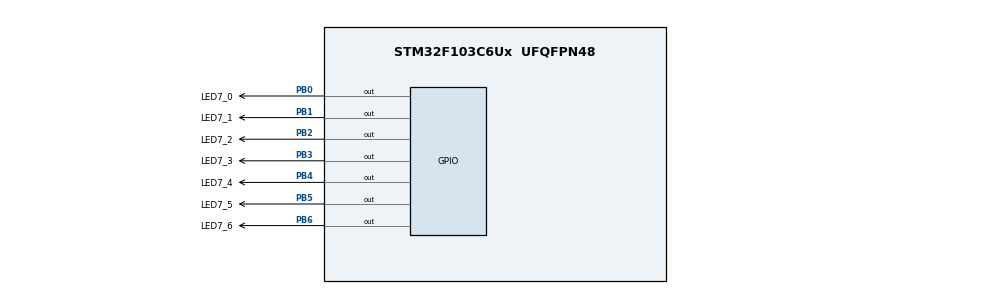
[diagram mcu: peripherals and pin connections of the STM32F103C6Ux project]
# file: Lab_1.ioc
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Mcu.Family=STM32F1
Mcu.Name=STM32F103C6Ux
Mcu.Package=UFQFPN48
NVIC.PriorityGroup=NVIC_PRIORITYGROUP_4
PB0.GPIO_Label=LED7_0
PB0.Signal=GPIO_Output
PB1.GPIO_Label=LED7_1
PB1.Signal=GPIO_Output
PB2.GPIO_Label=LED7_2
PB2.Signal=GPIO_Output
PB3.GPIO_Label=LED7_3
PB3.Signal=GPIO_Output
PB4.GPIO_Label=LED7_4
PB4.Signal=GPIO_Output
PB5.GPIO_Label=LED7_5
PB5.Signal=GPIO_Output
PB6.GPIO_Label=LED7_6
PB6.Signal=GPIO_Output
ProjectManager.HeapSize=0x200
ProjectManager.StackSize=0x400
ProjectManager.TargetToolchain=STM32CubeIDE
RCC.APB1Freq_Value=8000000
RCC.APB2Freq_Value=8000000
VP_SYS_VS_ND.Mode=No_Debug
board=custom

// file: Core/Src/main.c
/* USER CODE BEGIN Header */
/**
  ******************************************************************************
  * @file           : main.c
  * @brief          : Main program body
  ******************************************************************************
  * @attention
  *
  * <h2><center>&copy; Copyright (c) 2023 STMicroelectronics.
  * All rights reserved.</center></h2>
  *
  * This software component is licensed by ST under BSD 3-Clause license,
  * the "License"; You may not use this file except in compliance with the
  * License. You may obtain a copy of the License at:
  *                        opensource.org/licenses/BSD-3-Clause
  *
  ******************************************************************************
  */
/* USER CODE END Header */
#include "main.h"

void SystemClock_Config(void);
static void MX_GPIO_Init(void);
void clearAllClock();
void setNumberOnClock(int num);
void clearNumberOnClock(int num);

int main(void)
{

  /* MCU Configuration--------------------------------------------------------*/

  /* Reset of all peripherals, Initializes the Flash interface and the Systick. */
  HAL_Init();

  /* Configure the system clock */
  SystemClock_Config();

  /* Initialize all configured peripherals */
  MX_GPIO_Init();

  /* Infinite loop */
  //Quy ước:
  /* Mỗi 5 giây -> LED hiển thị giây di chuyển 1đv*/
  /* Mỗi 60 giây (LED hiển thị giây quay 1 vòng) -> LED hiển thị phút di chuyển 1đv */
  /* LED hiển thị phút quay 1 vòng -> LED hiển thị giờ di chuyển 1đv */
  /* không giống với thực tế vì để giảm thời gian kiểm tra */
  clearAllClock();
  int second = 0, minute = 10, hour = 5; // start at 5:10:00
  int counter = 0;
  while (1)
  {
	  setNumberOnClock(second);
	  setNumberOnClock(minute);
	  setNumberOnClock(hour);
	  HAL_Delay(1000);
	  counter ++;
	  if(counter >= 5){
		  counter = 0;
		  clearNumberOnClock(second++);
	  }
	  if(second >= 12){
		  second = 0;
		  clearNumberOnClock(minute++);
	  }
	  if(minute >= 12){
		  minute = 0;
		  clearNumberOnClock(hour++);
	  }
	  if(hour >= 12) hour = 0;
  }
}

void clearAllClock(){
	HAL_GPIO_WritePin (GPIOA , LED_1_Pin | LED_2_Pin | LED_3_Pin | LED_4_Pin | LED_5_Pin | LED_6_Pin | LED_7_Pin | LED_8_Pin | LED_9_Pin | LED_10_Pin | LED_11_Pin | LED_12_Pin , 1);
}

void setNumberOnClock(int num){
	switch(num){
	case 0:
		HAL_GPIO_WritePin(GPIOA, LED_12_Pin, 0);
		break;
	case 1:
		HAL_GPIO_WritePin(GPIOA, LED_1_Pin, 0);
		break;
	case 2:
		HAL_GPIO_WritePin(GPIOA, LED_2_Pin, 0);
		break;
	case 3:
		HAL_GPIO_WritePin(GPIOA, LED_3_Pin, 0);
		break;
	case 4:
		HAL_GPIO_WritePin(GPIOA, LED_4_Pin, 0);
		break;
	case 5:
		HAL_GPIO_WritePin(GPIOA, LED_5_Pin, 0);
		break;
	case 6:
		HAL_GPIO_WritePin(GPIOA, LED_6_Pin, 0);
		break;
	case 7:
		HAL_GPIO_WritePin(GPIOA, LED_7_Pin, 0);
		break;
	case 8:
		HAL_GPIO_WritePin(GPIOA, LED_8_Pin, 0);
		break;
	case 9:
		HAL_GPIO_WritePin(GPIOA, LED_9_Pin, 0);
		break;
	case 10:
		HAL_GPIO_WritePin(GPIOA, LED_10_Pin, 0);
		break;
	case 11:
		HAL_GPIO_WritePin(GPIOA, LED_11_Pin, 0);
		break;
	default:
		break;
	}
}

void clearNumberOnClock(int num){
	switch(num){
	case 0:
		HAL_GPIO_WritePin(GPIOA, LED_12_Pin, 1);
		break;
	case 1:
		HAL_GPIO_WritePin(GPIOA, LED_1_Pin, 1);
		break;
	case 2:
		HAL_GPIO_WritePin(GPIOA, LED_2_Pin, 1);
		break;
	case 3:
		HAL_GPIO_WritePin(GPIOA, LED_3_Pin, 1);
		break;
	case 4:
		HAL_GPIO_WritePin(GPIOA, LED_4_Pin, 1);
		break;
	case 5:
		HAL_GPIO_WritePin(GPIOA, LED_5_Pin, 1);
		break;
	case 6:
		HAL_GPIO_WritePin(GPIOA, LED_6_Pin, 1);
		break;
	case 7:
		HAL_GPIO_WritePin(GPIOA, LED_7_Pin, 1);
		break;
	case 8:
		HAL_GPIO_WritePin(GPIOA, LED_8_Pin, 1);
		break;
	case 9:
		HAL_GPIO_WritePin(GPIOA, LED_9_Pin, 1);
		break;
	case 10:
		HAL_GPIO_WritePin(GPIOA, LED_10_Pin, 1);
		break;
	case 11:
		HAL_GPIO_WritePin(GPIOA, LED_11_Pin, 1);
		break;
	default:
		break;
	}
}

void SystemClock_Config(void)
{
  RCC_OscInitTypeDef RCC_OscInitStruct = {0};
  RCC_ClkInitTypeDef RCC_ClkInitStruct = {0};

  /** Initializes the RCC Oscillators according to the specified parameters
  * in the RCC_OscInitTypeDef structure.
  */
  RCC_OscInitStruct.OscillatorType = RCC_OSCILLATORTYPE_HSI;
  RCC_OscInitStruct.HSIState = RCC_HSI_ON;
  RCC_OscInitStruct.HSICalibrationValue = RCC_HSICALIBRATION_DEFAULT;
  RCC_OscInitStruct.PLL.PLLState = RCC_PLL_NONE;
  if (HAL_RCC_OscConfig(&RCC_OscInitStruct) != HAL_OK)
  {
    Error_Handler();
  }
  /** Initializes the CPU, AHB and APB buses clocks
  */
  RCC_ClkInitStruct.ClockType = RCC_CLOCKTYPE_HCLK|RCC_CLOCKTYPE_SYSCLK
                              |RCC_CLOCKTYPE_PCLK1|RCC_CLOCKTYPE_PCLK2;
  RCC_ClkInitStruct.SYSCLKSource = RCC_SYSCLKSOURCE_HSI;
  RCC_ClkInitStruct.AHBCLKDivider = RCC_SYSCLK_DIV1;
  RCC_ClkInitStruct.APB1CLKDivider = RCC_HCLK_DIV1;
  RCC_ClkInitStruct.APB2CLKDivider = RCC_HCLK_DIV1;

  if (HAL_RCC_ClockConfig(&RCC_ClkInitStruct, FLASH_LATENCY_0) != HAL_OK)
  {
    Error_Handler();
  }
}

static void MX_GPIO_Init(void)
{
  GPIO_InitTypeDef GPIO_InitStruct = {0};

  /* GPIO Ports Clock Enable */
  __HAL_RCC_GPIOA_CLK_ENABLE();

  /*Configure GPIO pin Output Level */
  HAL_GPIO_WritePin(GPIOA, LED_1_Pin|LED_2_Pin|LED_3_Pin|LED_4_Pin
                          |LED_5_Pin|LED_6_Pin|LED_7_Pin|LED_8_Pin
                          |LED_9_Pin|LED_10_Pin|LED_11_Pin|LED_12_Pin, GPIO_PIN_RESET);

  /*Configure GPIO pins : LED_1_Pin LED_2_Pin LED_3_Pin LED_4_Pin
                           LED_5_Pin LED_6_Pin LED_7_Pin LED_8_Pin
                           LED_9_Pin LED_10_Pin LED_11_Pin LED_12_Pin */
  GPIO_InitStruct.Pin = LED_1_Pin|LED_2_Pin|LED_3_Pin|LED_4_Pin
                          |LED_5_Pin|LED_6_Pin|LED_7_Pin|LED_8_Pin
                          |LED_9_Pin|LED_10_Pin|LED_11_Pin|LED_12_Pin;
  GPIO_InitStruct.Mode = GPIO_MODE_OUTPUT_PP;
  GPIO_InitStruct.Pull = GPIO_NOPULL;
  GPIO_InitStruct.Speed = GPIO_SPEED_FREQ_LOW;
  HAL_GPIO_Init(GPIOA, &GPIO_InitStruct);

}

void Error_Handler(void)
{
  __disable_irq();
  while (1)
  {
  }
}

/************************ (C) COPYRIGHT STMicroelectronics *****END OF FILE****/
